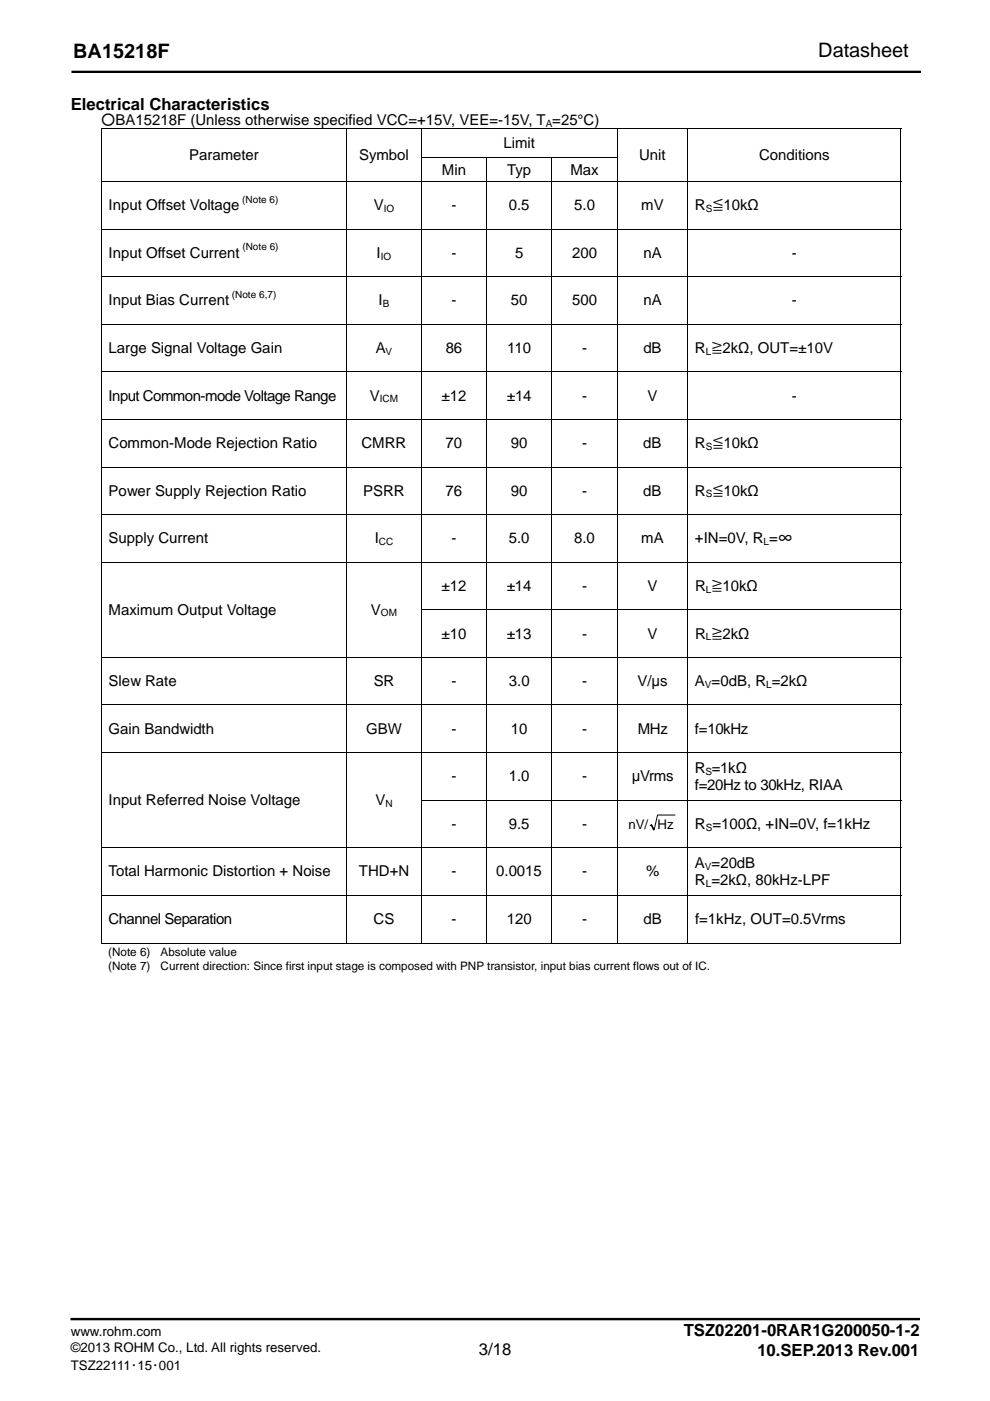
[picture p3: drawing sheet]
<svg xmlns="http://www.w3.org/2000/svg" width="210mm" height="297mm" viewBox="0 0 210 297" stroke-linecap="round" stroke-linejoin="round" font-family="sans-serif">
<defs><g id="words">
<g font-size="4.2">
<text x="15.5" y="12.4">BA15218F</text>
<text x="173.6" y="12.1">Datasheet</text>
</g>
<g font-size="3.5">
<text x="15" y="23.3">Electrical Characteristics</text>
<text x="101.6" y="287.3">3/18</text>
<text x="145" y="283.4">TSZ02201-0RAR1G200050-1-2</text>
<text x="160.6" y="287.4">10.SEP.2013 Rev.001</text>
</g>
<g font-size="3.2">
<text x="21.4" y="26.6">○BA15218F (Unless otherwise specified VCC=+15V, VEE=-15V, T =25°C)</text>
<text x="40.1" y="34">Parameter</text>
<text x="76.2" y="34">Symbol</text>
<text x="106.8" y="31.4">Limit</text>
<text x="135.6" y="34">Unit</text>
<text x="161" y="34">Conditions</text>
<text x="93.7" y="37">Min</text>
<text x="107.6" y="37">Typ</text>
<text x="121" y="37">Max</text>
<text x="23" y="44.6">Input Offset Voltage</text>
<text x="79.3" y="44.6">V</text>
<text x="95.8" y="44.6">-</text>
<text x="107.9" y="44.6">0.5</text>
<text x="121.8" y="44.6">5.0</text>
<text x="136" y="44.6">mV</text>
<text x="147.4" y="44.6">R ≦10kΩ</text>
<text x="23" y="54.7">Input Offset Current</text>
<text x="79.9" y="54.7">I</text>
<text x="95.8" y="54.7">-</text>
<text x="109.2" y="54.7">5</text>
<text x="121.3" y="54.7">200</text>
<text x="136.5" y="54.7">nA</text>
<text x="168" y="54.7">-</text>
<text x="23" y="64.7">Input Bias Current</text>
<text x="80.3" y="64.7">I</text>
<text x="95.8" y="64.7">-</text>
<text x="108.3" y="64.7">50</text>
<text x="121.3" y="64.7">500</text>
<text x="136.5" y="64.7">nA</text>
<text x="168" y="64.7">-</text>
<text x="23" y="74.8">Large Signal Voltage Gain</text>
<text x="79.7" y="74.8">A</text>
<text x="94.5" y="74.8">86</text>
<text x="107.6" y="74.8">110</text>
<text x="123.5" y="74.8">-</text>
<text x="136.5" y="74.8">dB</text>
<text x="147.4" y="74.8">R ≧2kΩ, OUT=±10V</text>
<text x="23" y="84.9">Input Common-mode Voltage Range</text>
<text x="78.4" y="84.9">V</text>
<text x="93.7" y="84.9">±12</text>
<text x="107.5" y="84.9">±14</text>
<text x="123.5" y="84.9">-</text>
<text x="137.4" y="84.9">V</text>
<text x="168" y="84.9">-</text>
<text x="23" y="95">Common-Mode Rejection Ratio</text>
<text x="76.7" y="95">CMRR</text>
<text x="94.5" y="95">70</text>
<text x="108.3" y="95">90</text>
<text x="123.5" y="95">-</text>
<text x="136.4" y="95">dB</text>
<text x="147.4" y="95">R ≦10kΩ</text>
<text x="23" y="105.1">Power Supply Rejection Ratio</text>
<text x="77" y="105.1">PSRR</text>
<text x="94.5" y="105.1">76</text>
<text x="108.3" y="105.1">90</text>
<text x="123.4" y="105.1">-</text>
<text x="136.4" y="105.1">dB</text>
<text x="147.4" y="105.1">R ≦10kΩ</text>
<text x="23" y="115.2">Supply Current</text>
<text x="79.5" y="115.2">I</text>
<text x="95.8" y="115.2">-</text>
<text x="107.9" y="115.2">5.0</text>
<text x="121.8" y="115.2">8.0</text>
<text x="136" y="115.2">mA</text>
<text x="147.4" y="115.2">+IN=0V, R =∞</text>
<text x="93.7" y="125.3">±12</text>
<text x="107.5" y="125.3">±14</text>
<text x="123.5" y="125.3">-</text>
<text x="137.4" y="125.3">V</text>
<text x="147.4" y="125.3">R ≧10kΩ</text>
<text x="23" y="130.3">Maximum Output Voltage</text>
<text x="78.7" y="130.3">V</text>
<text x="93.7" y="135.4">±10</text>
<text x="107.5" y="135.4">±13</text>
<text x="123.5" y="135.4">-</text>
<text x="137.4" y="135.4">V</text>
<text x="147.4" y="135.4">R ≧2kΩ</text>
<text x="23" y="145.5">Slew Rate</text>
<text x="79.3" y="145.5">SR</text>
<text x="95.8" y="145.5">-</text>
<text x="107.9" y="145.5">3.0</text>
<text x="123.5" y="145.5">-</text>
<text x="135.2" y="145.5">V/μs</text>
<text x="147.4" y="145.5">A =0dB, R =2kΩ</text>
<text x="23" y="155.6">Gain Bandwidth</text>
<text x="77.7" y="155.6">GBW</text>
<text x="95.8" y="155.6">-</text>
<text x="108.4" y="155.6">10</text>
<text x="123.5" y="155.6">-</text>
<text x="135.3" y="155.6">MHz</text>
<text x="147.4" y="155.6">f=10kHz</text>
<text x="95.8" y="165.6">-</text>
<text x="107.9" y="165.6">1.0</text>
<text x="123.5" y="165.6">-</text>
<text x="134" y="165.6">μVrms</text>
<text x="147.4" y="163.9">R =1kΩ</text>
<text x="147.4" y="167.4">f=20Hz to 30kHz, RIAA</text>
<text x="23" y="170.7">Input Referred Noise Voltage</text>
<text x="79.6" y="170.7">V</text>
<text x="95.8" y="175.7">-</text>
<text x="107.9" y="175.7">9.5</text>
<text x="123.5" y="175.7">-</text>
<text x="147.4" y="175.7">R =100Ω, +IN=0V, f=1kHz</text>
<text x="23" y="185.8">Total Harmonic Distortion + Noise</text>
<text x="76.1" y="185.8">THD+N</text>
<text x="95.7" y="185.8">-</text>
<text x="105.2" y="185.8">0.0015</text>
<text x="123.5" y="185.8">-</text>
<text x="137" y="185.8">%</text>
<text x="147.4" y="184.1">A =20dB</text>
<text x="147.4" y="187.7">R =2kΩ, 80kHz-LPF</text>
<text x="23" y="195.9">Channel Separation</text>
<text x="79.2" y="195.9">CS</text>
<text x="95.8" y="195.9">-</text>
<text x="107.5" y="195.9">120</text>
<text x="123.5" y="195.9">-</text>
<text x="136.5" y="195.9">dB</text>
<text x="147.4" y="195.9">f=1kHz, OUT=0.5Vrms</text>
</g>
<g font-size="2.8">
<text x="133.3" y="175.7">nV/ Hz</text>
<text x="15" y="283.4">www.rohm.com</text>
<text x="15" y="286.7">©2013 ROHM Co., Ltd. All rights reserved.</text>
<text x="15" y="290.4">TSZ22111･15･001</text>
</g>
<g font-size="2.5">
<text x="22.9" y="202.6">(Note 6)</text>
<text x="34.1" y="202.6">Absolute value</text>
<text x="22.9" y="205.8">(Note 7)</text>
<text x="34.1" y="205.8">Current direction: Since first input stage is composed with PNP transistor, input bias current flows out of IC.</text>
</g>
<g font-size="2.1">
<text x="115.7" y="27">A</text>
<text x="51.4" y="43">(Note 6)</text>
<text x="81.4" y="44.9">IO</text>
<text x="149.7" y="44.9">S</text>
<text x="51.4" y="53.1">(Note 6)</text>
<text x="80.8" y="55">IO</text>
<text x="49.2" y="63.2">(Note 6,7)</text>
<text x="81.2" y="65.1">B</text>
<text x="81.8" y="75.2">V</text>
<text x="149.7" y="75.2">L</text>
<text x="80.6" y="85.3">ICM</text>
<text x="149.7" y="95.4">S</text>
<text x="149.7" y="105.5">S</text>
<text x="80.4" y="115.6">CC</text>
<text x="161.9" y="115.6">L</text>
<text x="149.7" y="125.6">L</text>
<text x="80.8" y="130.7">OM</text>
<text x="149.7" y="135.7">L</text>
<text x="149.5" y="145.8">V</text>
<text x="162.5" y="145.8">L</text>
<text x="149.6" y="164.3">S</text>
<text x="81.7" y="171">N</text>
<text x="149.7" y="176.1">S</text>
<text x="149.5" y="184.5">V</text>
<text x="149.7" y="188">L</text>
</g>
</g></defs>
<path d="M15.3 15.2h179.9" fill="none" stroke="#000" stroke-width=".3"/>
<g fill="none" stroke="#000" stroke-width=".21">
<path d="M15.3 15.1h179.9v.3h-179.9zM21.4 27.3h169.8M21.4 38.5h169.8M21.5 27.4v6M21.5 33.4v5M21.5 38.5v10M73.5 27.4v6M73.5 33.4v5M73.5 38.5v10M89.3 33.4h41.7M89.4 27.4v6M89.4 33.4v5"/>
<path d="M89.4 38.5v10M103.2 33.4v5M103.2 38.5v10M117.1 33.4v5M117.1 38.5v10M130.9 27.4v6M130.9 33.4v5M130.9 38.5v10M145.9 27.4v6M145.9 33.4v5M145.9 38.5v10M191.1 27.4v6"/>
<path d="M191.1 33.4v5M191.1 38.5v10M21.4 48.6h169.8M21.4 58.7h169.8M21.5 48.6v10M21.5 58.7v10M73.5 48.6v10M73.5 58.7v10M89.4 48.6v10M89.4 58.7v10M103.2 48.6v10M103.2 58.7v10"/>
<path d="M117.1 48.6v10M117.1 58.7v10M130.9 48.6v10M130.9 58.7v10M145.9 48.6v10M145.9 58.7v10M191.1 48.6v10M191.1 58.7v10M21.4 68.7h169.8M21.4 78.8h169.8M21.5 68.8v10M21.5 78.9v10"/>
<path d="M73.5 68.8v10M73.5 78.9v10M89.4 68.8v10M89.4 78.9v10M103.2 68.8v10M103.2 78.9v10M117.1 68.8v10M117.1 78.9v10M130.9 68.8v10M130.9 78.9v10M145.9 68.8v10M145.9 78.9v10"/>
<path d="M191.1 68.8v10M191.1 78.9v10M21.4 88.9h169.8M21.4 99h169.8M21.5 89v10M21.5 99.1v10M73.5 89v10M73.5 99.1v10M89.4 89v10M89.4 99.1v10M103.2 89v10M103.2 99.1v10"/>
<path d="M117.1 89v10M117.1 99.1v10M130.9 89v10M130.9 99.1v10M145.9 89v10M145.9 99.1v10M191.1 89v10M191.1 99.1v10M21.4 109.1h169.8M21.4 119.2h169.8M21.5 109.2v9.9M21.5 119.2v10"/>
<path d="M73.5 109.2v9.9M73.5 119.2v10M89.4 109.2v9.9M89.4 119.2v10M103.2 109.2v9.9M103.2 119.2v10M117.1 109.2v9.9M117.1 119.2v10M130.9 109.2v9.9M130.9 119.2v10M145.9 109.2v9.9M145.9 119.2v10"/>
<path d="M191.1 109.2v9.9M191.1 119.2v10M21.4 139.4h169.8M21.5 129.3v10M21.5 139.4v10M73.5 129.3v10M73.5 139.4v10M89.3 129.3h101.9M89.4 129.3v10M89.4 139.4v10M103.2 129.3v10M103.2 139.4v10"/>
<path d="M117.1 129.3v10M117.1 139.4v10M130.9 129.3v10M130.9 139.4v10M145.9 129.3v10M145.9 139.4v10M191.1 129.3v10M191.1 139.4v10M21.4 149.5h169.8M21.4 159.6h169.8M21.5 149.5v10M21.5 159.6v10"/>
<path d="M73.5 149.5v10M73.5 159.6v10M89.4 149.5v10M89.4 159.6v10M103.2 149.5v10M103.2 159.6v10M117.1 149.5v10M117.1 159.6v10M130.9 149.5v10M130.9 159.6v10M145.9 149.5v10M145.9 159.6v10"/>
<path d="M191.1 149.5v10M191.1 159.6v10M21.4 179.7h169.8M21.5 169.7v10M21.5 179.8v10M73.5 169.7v10M73.5 179.8v10M89.3 169.7h101.9M89.4 169.7v10M89.4 179.8v10M103.2 169.7v10M103.2 179.8v10"/>
<path d="M117.1 169.7v10M117.1 179.8v10M130.9 169.7v10M130.9 179.8v10M138.2 174.9l-.3 .2M143.2 172.8h-3.7l-.8 3.1M145.9 169.7v10M145.9 179.8v10M191.1 169.7v10M191.1 179.8v10M21.4 189.8h169.8M21.4 200h169.6"/>
<path d="M21.5 189.9v10.1M73.5 189.9v10M89.4 189.9v10M103.2 189.9v10M117.1 189.9v10M130.9 189.9v10M145.9 189.9v10M191.1 189.9v10.1M15 279.5h180v.3h-180z"/>
</g>
<path d="M15.1 279.7h179.9" fill="none" stroke="#000" stroke-width=".28"/>
<path d="M21.4 27.2h.2v.2h-.2zM21.4 33.4h.2zM73.5 33.4h.1zM191 27.2h.2v.2h-.2zM191 33.4h.2zM21.4 129.2l.2 .1zM73.5 129.2l.1 .1zM21.4 169.6l.2 .1zM73.5 169.6l.1 .1zM191 199.9h.2v.1h-.2z" fill="#000"/>
<path d="M138.2 174.9l.5 1" fill="none" stroke="#000" stroke-width=".35"/>
<use href="#words"/>
</svg>
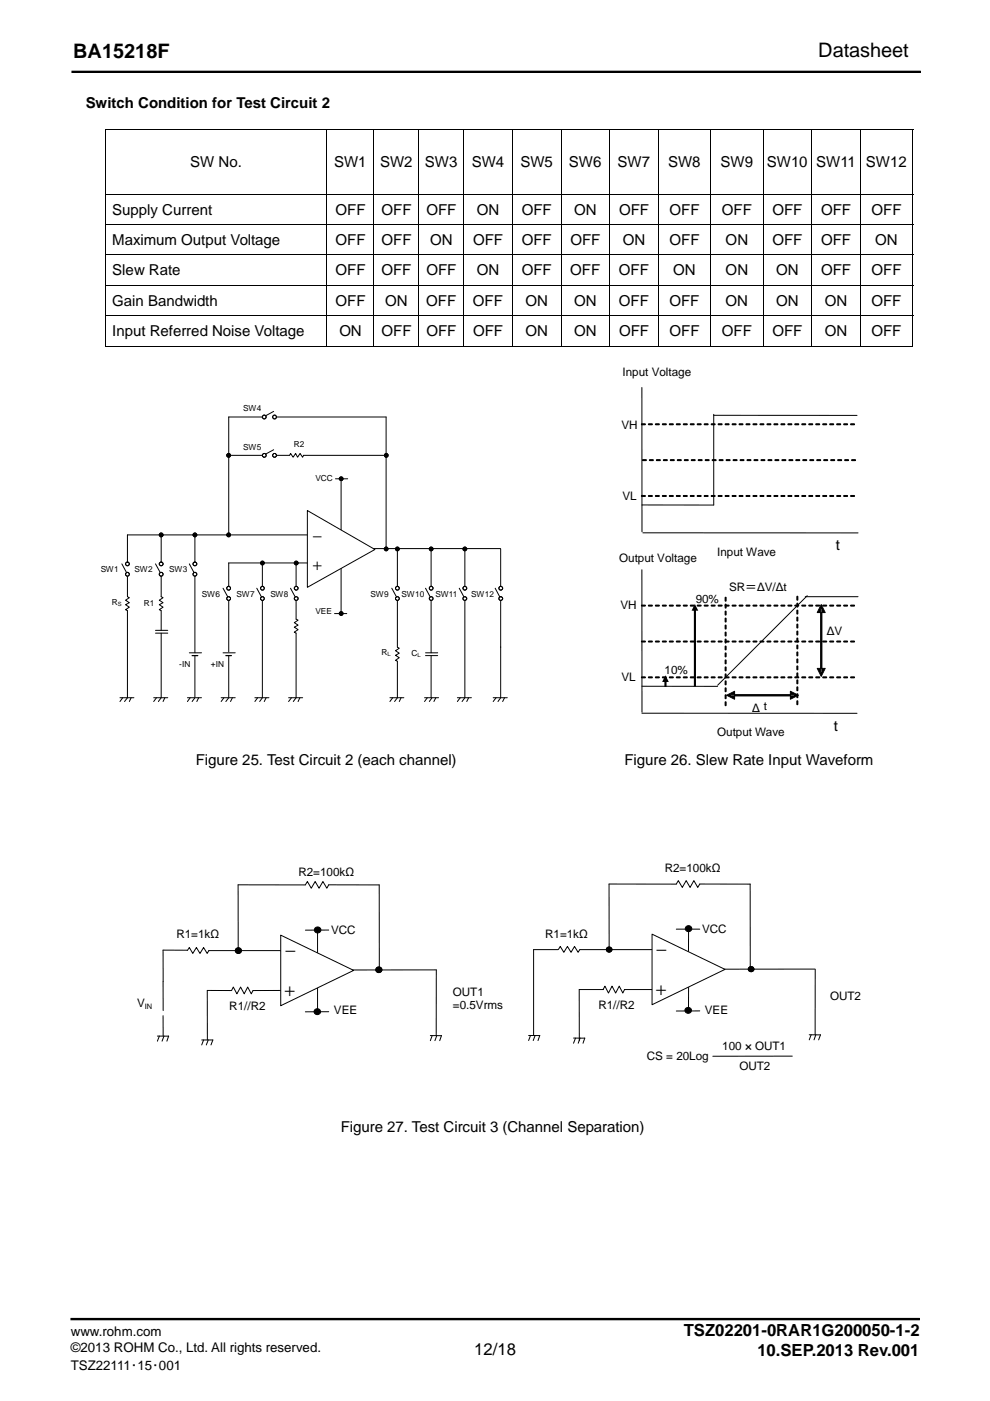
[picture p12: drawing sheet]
<svg xmlns="http://www.w3.org/2000/svg" width="210mm" height="297mm" viewBox="0 0 210 297" stroke-linecap="round" stroke-linejoin="round" font-family="sans-serif">
<defs><g id="words">
<g font-size="4.2">
<text x="15.5" y="12.4">BA15218F</text>
<text x="173.6" y="12.1">Datasheet</text>
</g>
<g font-size="3.5">
<text x="100.6" y="287.3">12/18</text>
<text x="145" y="283.4">TSZ02201-0RAR1G200050-1-2</text>
<text x="160.6" y="287.4">10.SEP.2013 Rev.001</text>
</g>
<g font-size="3.2">
<text x="18.2" y="22.9">Switch Condition for Test Circuit 2</text>
<text x="40.4" y="35.4">SW No.</text>
<text x="70.9" y="35.4">SW1</text>
<text x="80.6" y="35.4">SW2</text>
<text x="90.1" y="35.4">SW3</text>
<text x="100" y="35.4">SW4</text>
<text x="110.4" y="35.4">SW5</text>
<text x="120.7" y="35.4">SW6</text>
<text x="131" y="35.4">SW7</text>
<text x="141.7" y="35.4">SW8</text>
<text x="152.8" y="35.4">SW9</text>
<text x="162.7" y="35.4">SW10 SW11 SW12</text>
<text x="23.8" y="45.5">Supply Current</text>
<text x="71.2" y="45.5">OFF</text>
<text x="80.9" y="45.5">OFF</text>
<text x="90.4" y="45.5">OFF</text>
<text x="101.1" y="45.5">ON</text>
<text x="110.7" y="45.5">OFF</text>
<text x="121.8" y="45.5">ON</text>
<text x="131.3" y="45.5">OFF</text>
<text x="142" y="45.5">OFF</text>
<text x="153.1" y="45.5">OFF</text>
<text x="163.8" y="45.5">OFF</text>
<text x="174.2" y="45.5">OFF</text>
<text x="184.9" y="45.5">OFF</text>
<text x="23.8" y="51.9">Maximum Output Voltage</text>
<text x="71.2" y="51.9">OFF</text>
<text x="80.9" y="51.9">OFF</text>
<text x="91.2" y="51.9">ON</text>
<text x="100.3" y="51.9">OFF</text>
<text x="110.7" y="51.9">OFF</text>
<text x="121" y="51.9">OFF</text>
<text x="132.1" y="51.9">ON</text>
<text x="142" y="51.9">OFF</text>
<text x="153.9" y="51.9">ON</text>
<text x="163.8" y="51.9">OFF</text>
<text x="174.2" y="51.9">OFF</text>
<text x="185.6" y="51.9">ON</text>
<text x="23.8" y="58.4">Slew Rate</text>
<text x="71.2" y="58.4">OFF</text>
<text x="80.9" y="58.4">OFF</text>
<text x="90.4" y="58.4">OFF</text>
<text x="101.1" y="58.4">ON</text>
<text x="110.7" y="58.4">OFF</text>
<text x="121" y="58.4">OFF</text>
<text x="131.3" y="58.4">OFF</text>
<text x="142.8" y="58.4">ON</text>
<text x="153.9" y="58.4">ON</text>
<text x="164.6" y="58.4">ON</text>
<text x="174.2" y="58.4">OFF</text>
<text x="184.9" y="58.4">OFF</text>
<text x="23.8" y="64.8">Gain Bandwidth</text>
<text x="71.2" y="64.8">OFF</text>
<text x="81.7" y="64.8">ON</text>
<text x="90.4" y="64.8">OFF</text>
<text x="100.3" y="64.8">OFF</text>
<text x="111.4" y="64.8">ON</text>
<text x="121.7" y="64.8">ON</text>
<text x="131.3" y="64.8">OFF</text>
<text x="142" y="64.8">OFF</text>
<text x="153.9" y="64.8">ON</text>
<text x="164.6" y="64.8">ON</text>
<text x="175" y="64.8">ON</text>
<text x="184.8" y="64.8">OFF</text>
<text x="23.8" y="71.3">Input Referred Noise Voltage</text>
<text x="72" y="71.3">ON</text>
<text x="80.9" y="71.3">OFF</text>
<text x="90.4" y="71.3">OFF</text>
<text x="100.3" y="71.3">OFF</text>
<text x="111.5" y="71.3">ON</text>
<text x="121.8" y="71.3">ON</text>
<text x="131.3" y="71.3">OFF</text>
<text x="142" y="71.3">OFF</text>
<text x="153.1" y="71.3">OFF</text>
<text x="163.8" y="71.3">OFF</text>
<text x="175" y="71.3">ON</text>
<text x="184.8" y="71.3">OFF</text>
<text x="177.2" y="116.7">t</text>
<text x="176.8" y="154.9">t</text>
<text x="41.5" y="162.3">Figure 25. Test Circuit 2 (each channel)</text>
<text x="132.4" y="162.2">Figure 26. Slew Rate Input Waveform</text>
<text x="72.3" y="239.9">Figure 27. Test Circuit 3 (Channel Separation)</text>
</g>
<g font-size="2.8">
<text x="60.2" y="202.7">－</text>
<text x="138.9" y="202.5">－</text>
<text x="60.1" y="211.2">＋</text>
<text x="138.9" y="211">＋</text>
<text x="15" y="283.4">www.rohm.com</text>
<text x="15" y="286.7">©2013 ROHM Co., Ltd. All rights reserved.</text>
<text x="15" y="290.4">TSZ22111･15･001</text>
</g>
<g font-size="2.5">
<text x="132" y="79.8">Input Voltage</text>
<text x="131.8" y="90.9">VH</text>
<text x="132" y="106.1">VL</text>
<text x="66.1" y="114.6">－</text>
<text x="131.3" y="119.2">Output Voltage</text>
<text x="152.1" y="117.9">Input Wave</text>
<text x="66.1" y="120.8">＋</text>
<text x="154.6" y="125.3">SR＝ΔV/Δt</text>
<text x="131.6" y="129.1">VH</text>
<text x="147.6" y="127.9">90%</text>
<text x="175.3" y="134.6">ΔV</text>
<text x="140.9" y="143">10%</text>
<text x="131.8" y="144.3">VL</text>
<text x="159.5" y="150.9">Δ t</text>
<text x="152.1" y="156.1">Output Wave</text>
<text x="63.3" y="185.7">R2=100kΩ</text>
<text x="141" y="184.8">R2=100kΩ</text>
<text x="70.2" y="198">VCC</text>
<text x="148.9" y="197.7">VCC</text>
<text x="37.4" y="198.8">R1=1kΩ</text>
<text x="115.6" y="198.9">R1=1kΩ</text>
<text x="29.1" y="213.5">V</text>
<text x="48.6" y="214.2">R1//R2</text>
<text x="70.8" y="215.1">VEE</text>
<text x="96.1" y="211.1">OUT1</text>
<text x="96.1" y="213.8">=0.5Vrms</text>
<text x="126.9" y="213.8">R1//R2</text>
<text x="149.5" y="214.9">VEE</text>
<text x="176.1" y="212">OUT2</text>
<text x="137.2" y="224.7">CS = 20Log</text>
<text x="153.2" y="222.6">100 × OUT1</text>
<text x="156.8" y="226.8">OUT2</text>
</g>
<g font-size="1.8">
<text x="51.6" y="87.2">SW4</text>
<text x="51.6" y="95.5">SW5</text>
<text x="62.3" y="94.7">R2</text>
<text x="66.9" y="102">VCC</text>
<text x="21.4" y="121.3">SW1</text>
<text x="28.5" y="121.3">SW2</text>
<text x="35.9" y="121.3">SW3</text>
<text x="23.7" y="128.3">R</text>
<text x="30.5" y="128.4">R1</text>
<text x="42.8" y="126.5">SW6</text>
<text x="50.2" y="126.5">SW7</text>
<text x="57.3" y="126.5">SW8</text>
<text x="66.9" y="130.2">VEE</text>
<text x="78.6" y="126.7">SW9</text>
<text x="85.2" y="126.7">SW10</text>
<text x="92.4" y="126.7">SW11</text>
<text x="99.9" y="126.7">SW12</text>
<text x="38" y="141.4">-IN</text>
<text x="44.7" y="141.4">+IN</text>
<text x="80.9" y="138.9">R</text>
<text x="87.2" y="139.1">C</text>
</g>
<text font-size="1.6" x="30.7" y="213.8">IN</text>
<g font-size="1.2">
<text x="25" y="128.5">S</text>
<text x="82.2" y="139.1">L</text>
<text x="88.5" y="139.2">L</text>
</g>
</g></defs>
<path d="M15.3 15.2h179.9" fill="none" stroke="#000" stroke-width=".3"/>
<g fill="none" stroke="#000" stroke-width=".21">
<path d="M15.3 15.1h179.9v.3h-179.9zM22.2 27.4h171.5M22.3 27.5v4M22.3 31.5v9.6M69.3 27.5v4M69.3 31.5v9.6M79.3 27.5v4M79.3 31.5v9.6M88.8 27.5v4M88.8 31.5v9.6M98.4 27.5v4M98.4 31.5v9.6"/>
<path d="M108.7 27.5v4M108.7 31.5v9.6M119 27.5v4M119 31.5v9.6M129.3 27.5v4M129.3 31.5v9.6M139.6 27.5v4M139.6 31.5v9.6M150.7 27.5v4M150.7 31.5v9.6M161.9 27.5v4M161.9 31.5v9.6"/>
<path d="M172.2 27.5v4M172.2 31.5v9.6M182.5 27.5v4M182.5 31.5v9.6M193.6 27.5v4M193.6 31.5v9.6M22.2 41.2h171.5M22.2 47.6h171.5M22.2 54.1h171.5M22.3 41.2v6.4M22.3 47.6v6.4M22.3 54.1v6.4"/>
<path d="M69.3 41.2v6.4M69.3 47.6v6.4M69.3 54.1v6.4M79.3 41.2v6.4M79.3 47.6v6.4M79.3 54.1v6.4M88.8 41.2v6.4M88.8 47.6v6.4M88.8 54.1v6.4M98.4 41.2v6.4M98.4 47.6v6.4M98.4 54.1v6.4"/>
<path d="M108.7 41.2v6.4M108.7 47.6v6.4M108.7 54.1v6.4M119 41.2v6.4M119 47.6v6.4M119 54.1v6.4M129.3 41.2v6.4M129.3 47.6v6.4M129.3 54.1v6.4M139.6 41.2v6.4M139.6 47.6v6.4M139.6 54.1v6.4"/>
<path d="M150.7 41.2v6.4M150.7 47.6v6.4M150.7 54.1v6.4M161.9 41.2v6.4M161.9 47.6v6.4M161.9 54.1v6.4M172.2 41.2v6.4M172.2 47.6v6.4M172.2 54.1v6.4M182.5 41.2v6.4M182.5 47.6v6.4M182.5 54.1v6.4"/>
<path d="M193.6 41.2v6.4M193.6 47.6v6.4M193.6 54.1v6.4M22.2 60.5h171.5M22.2 66.9h171.5M22.2 73.4h171.3M22.3 60.5v6.4M22.3 67v6.5M69.3 60.5v6.4M69.3 67v6.3M79.3 60.5v6.4M79.3 67v6.3"/>
<path d="M88.8 60.5v6.4M88.8 67v6.3M98.4 60.5v6.4M98.4 67v6.3M108.7 60.5v6.4M108.7 67v6.3M119 60.5v6.4M119 67v6.3M129.3 60.5v6.4M129.3 67v6.3M139.6 60.5v6.4M139.6 67v6.3"/>
<path d="M150.7 60.5v6.4M150.7 67v6.3M161.9 60.5v6.4M161.9 67v6.3M172.2 60.5v6.4M172.2 67v6.3M182.5 60.5v6.4M182.5 67v6.3M193.6 60.5v6.4M193.6 67v6.5M136.1 89.9l.8 .1-.8 .1zM136.1 82.1l.1 30.7"/>
<path d="M136.3 97.5l.8 .1-.7 .1zM137.6 89.9l.8 .1-.8 .1zM137.8 97.5l.8 .1-.8 .1zM139 89.9l.8 .1-.7 .1zM139.3 97.5l.8 .1-.8 .1zM140.5 89.9l.8 .1-.7 .1zM140.7 97.5l.8 .1-.7 .1zM142 89.9l.8 .1-.7 .1zM142.2 97.5l.8 .1-.7 .1zM143.5 89.9l.8 .1-.7 .1zM143.7 97.5l.8 .1-.7 .1zM145 89.9l.8 .1-.8 .1z"/>
<path d="M145.2 97.5l.8 .1-.8 .1zM146.4 89.9l.8 .1-.7 .1zM146.7 97.5l.7 .1-.7 .1zM147.9 89.9l.8 .1-.7 .1zM148.1 97.5l.8 .1-.7 .1zM149.4 89.9l.8 .1-.7 .1zM149.6 97.5l.8 .1-.7 .1zM150.9 89.9l.8 .1-.8 .1zM151.1 97.5l.8 .1-.7 .1zM151.4 87.8v19.3h-15.3M151.4 88.1h30.4M152.3 89.9l.9 .1-.8 .1z"/>
<path d="M152.6 97.5l.8 .1-.8 .1zM153.8 89.9l.8 .1-.7 .1zM154 97.5l.9 .1-.8 .1zM155.3 89.9l.8 .1-.7 .1zM155.5 97.5l.8 .1-.7 .1zM156.8 89.9l.8 .1-.7 .1zM157 97.5l.8 .1-.7 .1zM158.3 89.9l.8 .1-.8 .1zM158.5 97.5l.8 .1-.8 .1zM159.7 89.9l.8 .1-.7 .1zM160 97.5l.8 .1-.8 .1zM161.2 89.9l.8 .1-.7 .1z"/>
<path d="M161.4 97.5l.8 .1-.7 .1zM162.7 89.9l.8 .1-.7 .1zM162.9 97.5l.8 .1-.7 .1zM164.2 89.9l.8 .1-.7 .1zM164.4 97.5l.8 .1-.7 .1zM165.7 89.9l.8 .1-.8 .1zM165.9 97.5l.8 .1-.8 .1zM167.1 89.9l.9 .1-.8 .1zM167.4 97.5l.8 .1-.8 .1zM168.6 89.9l.8 .1-.7 .1zM168.8 97.5l.8 .1-.7 .1zM170.1 89.9l.8 .1-.7 .1z"/>
<path d="M170.3 97.5l.8 .1-.7 .1zM171.6 89.9l.8 .1-.8 .1zM171.8 97.5l.8 .1-.7 .1zM173.1 89.9l.8 .1-.8 .1zM173.3 97.5l.8 .1-.8 .1zM174.5 89.9l.8 .1-.7 .1zM174.7 97.5l.9 .1-.8 .1zM176 89.9l.8 .1-.7 .1zM176.2 97.5l.8 .1-.7 .1zM177.5 89.9l.8 .1-.7 .1zM177.7 97.5l.8 .1-.7 .1zM179 89.9l.8 .1-.8 .1z"/>
<path d="M179.2 97.5l.8 .1-.7 .1zM180.4 89.9l.9 .1-.8 .1zM180.7 97.5l.8 .1-.8 .1zM27 113.4h43M41.3 113.4v6M48.5 119.4h22.9M72.2 116.3h34M72.3 101.5v28.2M136.1 105.1l.8 .1-.8 .1zM136.4 113h45.6M137.6 105.1l.8 .1-.8 .1zM139 105.1l.8 .1-.7 .1z"/>
<path d="M140.5 105.1l.8 .1-.7 .1zM142 105.1l.8 .1-.7 .1zM143.5 105.1l.8 .1-.7 .1zM145 105.1l.8 .1-.8 .1zM146.4 105.1l.8 .1-.7 .1zM147.9 105.1l.8 .1-.7 .1zM149.4 105.1l.8 .1-.7 .1zM150.9 105.1l.8 .1-.8 .1zM152.3 105.1l.9 .1-.8 .1zM153.8 105.1l.8 .1-.7 .1zM155.3 105.1l.8 .1-.7 .1zM156.8 105.1l.8 .1-.7 .1z"/>
<path d="M158.3 105.1l.8 .1-.8 .1zM159.7 105.1l.8 .1-.7 .1zM161.2 105.1l.8 .1-.7 .1zM162.7 105.1l.8 .1-.7 .1zM164.2 105.1l.8 .1-.7 .1zM165.7 105.1l.8 .1-.8 .1zM167.1 105.1l.9 .1-.8 .1zM168.6 105.1l.8 .1-.7 .1zM170.1 105.1l.8 .1-.7 .1zM171.6 105.1l.8 .1-.8 .1zM173.1 105.1l.8 .1-.8 .1zM174.5 105.1l.8 .1-.7 .1z"/>
<path d="M176 105.1l.8 .1-.7 .1zM177.5 105.1l.8 .1-.7 .1zM179 105.1l.8 .1-.8 .1zM180.4 105.1l.9 .1-.8 .1zM33 133.6h2.6M34.2 121.8v4.7M34.2 134.2v13.7M40.2 138.4h2.5M41.3 121.5v16.9M98.6 126.9v21M136.1 128.3l.8 .1-.8 .1zM136.1 135.9l.8 .1-.8 .1z"/>
<path d="M136.1 120.8l.1 30.2M137.6 128.3l.8 .1-.8 .1zM137.6 135.9l.8 .1-.8 .1zM139 128.3l.8 .1-.7 .1zM139 135.9l.8 .1-.7 .1zM140.5 128.3l.8 .1-.7 .1zM140.5 135.9l.8 .1-.7 .1zM142 128.3l.8 .1-.7 .1zM142 135.9l.8 .1-.7 .1zM143.5 128.3l.8 .1-.7 .1zM143.5 135.9l.8 .1-.7 .1zM145 128.3l.8 .1-.8 .1z"/>
<path d="M145 135.9l.8 .1-.8 .1zM146.4 128.3l.8 .1-.7 .1zM146.4 135.9l.8 .1-.7 .1zM147.9 128.3l.8 .1-.7 .1zM147.9 135.9l.8 .1-.7 .1zM149.4 128.3l.8 .1-.7 .1zM149.4 135.9l.8 .1-.7 .1zM150.9 128.3l.8 .1-.8 .1zM150.9 135.9l.8 .1-.8 .1zM152.3 128.3l.9 .1-.8 .1zM152.3 135.9l.9 .1-.8 .1zM153.8 126.6l.2 .1-.1 .8z"/>
<path d="M153.8 128.1l.2 .1-.1 .7zM153.8 129.6l.2 .1-.1 .7zM153.8 131.1h.2l-.1 .8zM153.8 132.6h.2l-.1 .8zM153.8 134l.2 .1-.1 .8zM153.8 135.5l.2 .1-.1 .7zM153.8 137l.2 .1-.1 .7zM153.8 138.5h.2l-.1 .8zM153.8 139.9l.2 .1-.1 .8zM153.8 128.3l.8 .1-.7 .1zM153.8 135.9l.8 .1-.7 .1zM155.3 128.3l.8 .1-.7 .1z"/>
<path d="M155.3 135.9l.8 .1-.7 .1zM156.8 128.3l.8 .1-.7 .1zM156.8 135.9l.8 .1-.7 .1zM158.3 128.3l.8 .1-.8 .1zM158.3 135.9l.8 .1-.8 .1zM159.7 128.3l.8 .1-.7 .1zM159.7 135.9l.8 .1-.7 .1zM161.2 128.3l.8 .1-.7 .1zM161.2 135.9l.8 .1-.7 .1zM162.7 128.3l.8 .1-.7 .1zM162.7 135.9l.8 .1-.7 .1zM164.2 128.3l.8 .1-.7 .1z"/>
<path d="M164.2 135.9l.8 .1-.7 .1zM165.7 128.3l.8 .1-.8 .1zM165.7 135.9l.8 .1-.8 .1zM167.1 128.3l.9 .1-.8 .1zM167.1 135.9l.9 .1-.8 .1zM168.6 128.3l.8 .1-.7 .1zM168.6 135.9l.8 .1-.7 .1zM169 126.4l.2 .1-.1 .8zM169 127.9l.2 .1-.1 .7zM169 129.4l.2 .1-.1 .7zM169 130.9h.2l-.1 .8zM169 132.3l.2 .1-.1 .8z"/>
<path d="M169 133.8l.2 .1-.1 .7zM169 135.3l.2 .1-.1 .7zM169 136.8l.2 .1-.1 .7zM169 138.3h.2l-.1 .8zM169 139.7l.2 .1-.1 .7zM170.1 128.3l.8 .1-.7 .1zM170.1 135.9l.8 .1-.7 .1zM170.8 126.5h11.2M171.2 126.3l-19 19M171.6 128.3l.8 .1-.8 .1zM171.6 135.9l.8 .1-.8 .1zM173.1 128.3l.8 .1-.8 .1z"/>
<path d="M173.1 135.9l.8 .1-.8 .1zM174.1 129l.2 .1v13.4l-.1 .1-.1-.1zM174.2 128.2l.8 1.7h-1.7zM174.5 128.3l.8 .1-.7 .1zM174.5 135.9l.8 .1-.7 .1zM176 128.3l.8 .1-.7 .1zM176 135.9l.8 .1-.7 .1zM177.5 128.3l.8 .1-.7 .1zM177.5 135.9l.8 .1-.7 .1zM179 128.3l.8 .1-.8 .1zM179 135.9l.8 .1-.8 .1zM180.4 128.3l.9 .1-.8 .1z"/>
<path d="M180.4 135.9l.9 .1-.8 .1zM136.1 143.5l.8 .1-.8 .1zM136.1 145.5h16.1M136.1 151.2h45.7M137.6 143.5l.8 .1-.8 .1zM139 143.5l.8 .1-.7 .1zM140.5 143.5l.8 .1-.7 .1zM142 143.5l.8 .1-.7 .1zM143.5 143.5l.8 .1-.7 .1zM145 143.5l.8 .1-.8 .1zM146.4 143.5l.8 .1-.7 .1zM147.9 143.5l.8 .1-.7 .1z"/>
<path d="M149.4 143.5l.8 .1-.7 .1zM150.9 143.5l.8 .1-.8 .1zM152.3 143.5l.9 .1-.8 .1zM153.8 141.4l.2 .1-.1 .7zM153.8 142.9l.2 .1-.1 .7zM153.8 144.4l.2 .1-.1 .7zM153.8 145.9h.2l-.1 .8zM153.8 147.3l.2 .1-.1 .7zM153.8 148.8l.2 .1-.1 .7zM153.8 143.5l.8 .1-.7 .1zM154.1 147.4l1.7-.8v1.7zM155 147.3h13.4l.2 .1-.2 .2h-13.3z"/>
<path d="M155.3 143.5l.8 .1-.7 .1zM156.8 143.5l.8 .1-.7 .1zM158.3 143.5l.8 .1-.8 .1zM159.7 143.5l.8 .1-.7 .1zM161.2 143.5l.8 .1-.7 .1zM162.7 143.5l.8 .1-.7 .1zM164.2 143.5l.8 .1-.7 .1zM165.7 143.5l.8 .1-.8 .1zM167.1 143.5l.9 .1-.8 .1zM167.6 146.6l1.7 .8-1.7 .9zM168.6 143.5l.8 .1-.7 .1zM169 141.2l.2 .1-.1 .7z"/>
<path d="M169 142.7l.2 .1-.1 .7zM169 144.2l.2 .1-.1 .7zM169 145.7h.2l-.1 .8zM169 147.1l.2 .1-.1 .7zM169 148.6l.2 .1-.1 .7zM170.1 143.5l.8 .1-.7 .1zM171.6 143.5l.8 .1-.8 .1zM173.1 143.5l.8 .1-.8 .1zM173.3 141.7h1.7l-.8 1.7zM174.5 143.5l.8 .1-.7 .1zM176 143.5l.8 .1-.7 .1zM177.5 143.5l.8 .1-.7 .1z"/>
<path d="M179 143.5l.8 .1-.8 .1zM180.4 143.5l.9 .1-.8 .1zM15 279.5h180v.3h-180z"/>
</g>
<path d="M15.1 279.7h179.9" fill="none" stroke="#000" stroke-width=".28"/>
<g fill="#000">
<path d="M22.2 27.3h.2v.2h-.2zM22.2 31.5h.2zM69.3 31.5h.1zM79.3 31.5h.1zM88.8 31.5h.1zM98.3 31.5h.1zM108.6 31.5h.1zM139.6 31.5h.1zM150.7 31.5h.1zM161.8 31.5h.1zM172.1 31.5h.1zM193.5 27.3h.2v.2h-.2z"/>
<path d="M193.5 31.5h.2zM193.5 73.3h.2v.2h-.2z"/>
<path d="M140.9 144.2h.5v1.4h-.5zM141.1 143.2l.8 1.4h-1.5z"/>
<path d="M147.2 129.1h.4v16.5h-.4zM147.4 128.1l.7 1.4h-1.4z"/>
</g>
<g fill="#000">
<path d="M136.1 89.9l.8 .1-.8 .1zM137.6 89.9l.8 .1-.8 .1zM139 89.9l.8 .1-.7 .1zM140.5 89.9l.8 .1-.7 .1zM142 89.9l.8 .1-.7 .1zM143.5 89.9l.8 .1-.7 .1zM145 89.9l.8 .1-.8 .1zM146.4 89.9l.8 .1-.7 .1zM147.9 89.9l.8 .1-.7 .1zM149.4 89.9l.8 .1-.7 .1zM150.9 89.9l.8 .1-.8 .1zM152.3 89.9l.9 .1-.8 .1zM153.8 89.9l.8 .1-.7 .1zM155.3 89.9l.8 .1-.7 .1zM156.8 89.9l.8 .1-.7 .1zM158.3 89.9l.8 .1-.8 .1zM159.7 89.9l.8 .1-.7 .1zM161.2 89.9l.8 .1-.7 .1zM162.7 89.9l.8 .1-.7 .1zM164.2 89.9l.8 .1-.7 .1zM165.7 89.9l.8 .1-.8 .1zM167.1 89.9l.9 .1-.8 .1zM168.6 89.9l.8 .1-.7 .1zM170.1 89.9l.8 .1-.7 .1zM171.6 89.9l.8 .1-.8 .1zM173.1 89.9l.8 .1-.8 .1zM174.5 89.9l.8 .1-.7 .1zM176 89.9l.8 .1-.7 .1zM177.5 89.9l.8 .1-.7 .1zM179 89.9l.8 .1-.8 .1zM180.4 89.9l.9 .1-.8 .1z" fill-rule="evenodd"/>
<path d="M136.3 97.5l.8 .1-.7 .1zM137.8 97.5l.8 .1-.8 .1zM139.3 97.5l.8 .1-.8 .1zM140.7 97.5l.8 .1-.7 .1zM142.2 97.5l.8 .1-.7 .1zM143.7 97.5l.8 .1-.7 .1zM145.2 97.5l.8 .1-.8 .1zM146.7 97.5l.7 .1-.7 .1zM148.1 97.5l.8 .1-.7 .1zM149.6 97.5l.8 .1-.7 .1zM151.1 97.5l.8 .1-.7 .1zM152.6 97.5l.8 .1-.8 .1zM154 97.5l.9 .1-.8 .1zM155.5 97.5l.8 .1-.7 .1zM157 97.5l.8 .1-.7 .1zM158.5 97.5l.8 .1-.8 .1zM160 97.5l.8 .1-.8 .1zM161.4 97.5l.8 .1-.7 .1zM162.9 97.5l.8 .1-.7 .1zM164.4 97.5l.8 .1-.7 .1zM165.9 97.5l.8 .1-.8 .1zM167.4 97.5l.8 .1-.8 .1zM168.8 97.5l.8 .1-.7 .1zM170.3 97.5l.8 .1-.7 .1zM171.8 97.5l.8 .1-.7 .1zM173.3 97.5l.8 .1-.8 .1zM174.7 97.5l.9 .1-.8 .1zM176.2 97.5l.8 .1-.7 .1zM177.7 97.5l.8 .1-.7 .1zM179.2 97.5l.8 .1-.7 .1zM180.7 97.5l.8 .1-.8 .1z" fill-rule="evenodd"/>
<path d="M136.1 105.1l.8 .1-.8 .1zM137.6 105.1l.8 .1-.8 .1zM139 105.1l.8 .1-.7 .1zM140.5 105.1l.8 .1-.7 .1zM142 105.1l.8 .1-.7 .1zM143.5 105.1l.8 .1-.7 .1zM145 105.1l.8 .1-.8 .1zM146.4 105.1l.8 .1-.7 .1zM147.9 105.1l.8 .1-.7 .1zM149.4 105.1l.8 .1-.7 .1zM150.9 105.1l.8 .1-.8 .1zM152.3 105.1l.9 .1-.8 .1zM153.8 105.1l.8 .1-.7 .1zM155.3 105.1l.8 .1-.7 .1zM156.8 105.1l.8 .1-.7 .1zM158.3 105.1l.8 .1-.8 .1zM159.7 105.1l.8 .1-.7 .1zM161.2 105.1l.8 .1-.7 .1zM162.7 105.1l.8 .1-.7 .1zM164.2 105.1l.8 .1-.7 .1zM165.7 105.1l.8 .1-.8 .1zM167.1 105.1l.9 .1-.8 .1zM168.6 105.1l.8 .1-.7 .1zM170.1 105.1l.8 .1-.7 .1zM171.6 105.1l.8 .1-.8 .1zM173.1 105.1l.8 .1-.8 .1zM174.5 105.1l.8 .1-.7 .1zM176 105.1l.8 .1-.7 .1zM177.5 105.1l.8 .1-.7 .1zM179 105.1l.8 .1-.8 .1zM180.4 105.1l.9 .1-.8 .1z" fill-rule="evenodd"/>
<path d="M136.1 128.3l.8 .1-.8 .1zM137.6 128.3l.8 .1-.8 .1zM139 128.3l.8 .1-.7 .1zM140.5 128.3l.8 .1-.7 .1zM142 128.3l.8 .1-.7 .1zM143.5 128.3l.8 .1-.7 .1zM145 128.3l.8 .1-.8 .1zM146.4 128.3l.8 .1-.7 .1zM147.9 128.3l.8 .1-.7 .1zM149.4 128.3l.8 .1-.7 .1zM150.9 128.3l.8 .1-.8 .1zM152.3 128.3l.9 .1-.8 .1zM153.8 128.3l.8 .1-.7 .1zM155.3 128.3l.8 .1-.7 .1zM156.8 128.3l.8 .1-.7 .1zM158.3 128.3l.8 .1-.8 .1zM159.7 128.3l.8 .1-.7 .1zM161.2 128.3l.8 .1-.7 .1zM162.7 128.3l.8 .1-.7 .1zM164.2 128.3l.8 .1-.7 .1zM165.7 128.3l.8 .1-.8 .1zM167.1 128.3l.9 .1-.8 .1zM168.6 128.3l.8 .1-.7 .1zM170.1 128.3l.8 .1-.7 .1zM171.6 128.3l.8 .1-.8 .1zM173.1 128.3l.8 .1-.8 .1zM174.5 128.3l.8 .1-.7 .1zM176 128.3l.8 .1-.7 .1zM177.5 128.3l.8 .1-.7 .1zM179 128.3l.8 .1-.8 .1zM180.4 128.3l.9 .1-.8 .1z" fill-rule="evenodd"/>
<path d="M136.1 135.9l.8 .1-.8 .1zM137.6 135.9l.8 .1-.8 .1zM139 135.9l.8 .1-.7 .1zM140.5 135.9l.8 .1-.7 .1zM142 135.9l.8 .1-.7 .1zM143.5 135.9l.8 .1-.7 .1zM145 135.9l.8 .1-.8 .1zM146.4 135.9l.8 .1-.7 .1zM147.9 135.9l.8 .1-.7 .1zM149.4 135.9l.8 .1-.7 .1zM150.9 135.9l.8 .1-.8 .1zM152.3 135.9l.9 .1-.8 .1zM153.8 135.9l.8 .1-.7 .1zM155.3 135.9l.8 .1-.7 .1zM156.8 135.9l.8 .1-.7 .1zM158.3 135.9l.8 .1-.8 .1zM159.7 135.9l.8 .1-.7 .1zM161.2 135.9l.8 .1-.7 .1zM162.7 135.9l.8 .1-.7 .1zM164.2 135.9l.8 .1-.7 .1zM165.7 135.9l.8 .1-.8 .1zM167.1 135.9l.9 .1-.8 .1zM168.6 135.9l.8 .1-.7 .1zM170.1 135.9l.8 .1-.7 .1zM171.6 135.9l.8 .1-.8 .1zM173.1 135.9l.8 .1-.8 .1zM174.5 135.9l.8 .1-.7 .1zM176 135.9l.8 .1-.7 .1zM177.5 135.9l.8 .1-.7 .1zM179 135.9l.8 .1-.8 .1zM180.4 135.9l.9 .1-.8 .1z" fill-rule="evenodd"/>
<path d="M153.8 126.6l.2 .1-.1 .8zM153.8 128.1l.2 .1-.1 .7zM153.8 129.6l.2 .1-.1 .7zM153.8 131.1h.2l-.1 .8zM153.8 132.6h.2l-.1 .8zM153.8 134l.2 .1-.1 .8zM153.8 135.5l.2 .1-.1 .7zM153.8 137l.2 .1-.1 .7zM153.8 138.5h.2l-.1 .8zM153.8 139.9l.2 .1-.1 .8zM153.8 141.4l.2 .1-.1 .7zM153.8 142.9l.2 .1-.1 .7zM153.8 144.4l.2 .1-.1 .7zM153.8 145.9h.2l-.1 .8zM153.8 147.3l.2 .1-.1 .7zM153.8 148.8l.2 .1-.1 .7z" fill-rule="evenodd"/>
<path d="M169 126.4l.2 .1-.1 .8zM169 127.9l.2 .1-.1 .7zM169 129.4l.2 .1-.1 .7zM169 130.9h.2l-.1 .8zM169 132.3l.2 .1-.1 .8zM169 133.8l.2 .1-.1 .7zM169 135.3l.2 .1-.1 .7zM169 136.8l.2 .1-.1 .7zM169 138.3h.2l-.1 .8zM169 139.7l.2 .1-.1 .7zM169 141.2l.2 .1-.1 .7zM169 142.7l.2 .1-.1 .7zM169 144.2l.2 .1-.1 .7zM169 145.7h.2l-.1 .8zM169 147.1l.2 .1-.1 .7zM169 148.6l.2 .1-.1 .7z" fill-rule="evenodd"/>
<path d="M136.1 143.5l.8 .1-.8 .1zM137.6 143.5l.8 .1-.8 .1zM139 143.5l.8 .1-.7 .1zM140.5 143.5l.8 .1-.7 .1zM142 143.5l.8 .1-.7 .1zM143.5 143.5l.8 .1-.7 .1zM145 143.5l.8 .1-.8 .1zM146.4 143.5l.8 .1-.7 .1zM147.9 143.5l.8 .1-.7 .1zM149.4 143.5l.8 .1-.7 .1zM150.9 143.5l.8 .1-.8 .1zM152.3 143.5l.9 .1-.8 .1zM153.8 143.5l.8 .1-.7 .1zM155.3 143.5l.8 .1-.7 .1zM156.8 143.5l.8 .1-.7 .1zM158.3 143.5l.8 .1-.8 .1zM159.7 143.5l.8 .1-.7 .1zM161.2 143.5l.8 .1-.7 .1zM162.7 143.5l.8 .1-.7 .1zM164.2 143.5l.8 .1-.7 .1zM165.7 143.5l.8 .1-.8 .1zM167.1 143.5l.9 .1-.8 .1zM168.6 143.5l.8 .1-.7 .1zM170.1 143.5l.8 .1-.7 .1zM171.6 143.5l.8 .1-.8 .1zM173.1 143.5l.8 .1-.8 .1zM174.5 143.5l.8 .1-.7 .1zM176 143.5l.8 .1-.7 .1zM177.5 143.5l.8 .1-.7 .1zM179 143.5l.8 .1-.8 .1zM180.4 143.5l.9 .1-.8 .1z" fill-rule="evenodd"/>
<path d="M155 147.3h13.4l.2 .1-.2 .2h-13.3zM154.1 147.4l1.7-.8v1.7zM167.6 146.6l1.7 .8-1.7 .9z" fill-rule="evenodd"/>
<path d="M174.1 129l.2 .1v13.4l-.1 .1-.1-.1zM173.3 141.7h1.7l-.8 1.7zM174.2 128.2l.8 1.7h-1.7z" fill-rule="evenodd"/>
</g>
<path d="M40.7 139h1.3" fill="none" stroke="#000" stroke-width=".26"/>
<path d="M65.2 108.2l14.3 8.3-14.3 8z" fill="#fff"/>
<g fill="none" stroke="#000" stroke-width=".21">
<path d="M27 113.4v6M33 119.5l1.2 2.3M34.2 113.4v6M65.2 108.2l14.3 8.3-14.3 8zM84.3 116.4v8.3M27 129.5v18.4l-.6 .8M33 134.2h2.6M34.2 126.5l.4 .2-.8 .6 .8 .5-.8 .4 .8 .5-.8 .6 .4 .2v4.1M71 130.1h2.6M84.3 127.1v10.1M91.4 126.7v11.7M25.4 147.9h3"/>
<path d="M26 147.9l-.6 .8M27.8 147.9l-.4 .8M32.6 147.9h3M33.2 147.9l-.6 .8M34.2 147.9l-.6 .8M35 147.9l-.4 .8M39.8 147.9h2.9M40.3 147.9l-.5 .8M41.3 147.9l-.6 .8M42.1 147.9l-.4 .8M82.7 147.9h3M83.3 147.9l-.6 .8"/>
<path d="M84.3 140.2v7.7l-.6 .8M85.1 147.9l-.4 .8M90 147.9h3M90.6 147.9l-.6 .8M91.6 147.9l-.5 .8M92.4 147.9l-.4 .8M97 147.9h3M97.6 147.9l-.6 .8M98.6 147.9l-.6 .8M99.4 147.9l-.4 .8"/>
<circle cx="34.2" cy="113.4" r=".4"/>
<circle cx="41.3" cy="113.4" r=".4"/>
<circle cx="72.4" cy="101.5" r=".39"/>
<circle cx="84.3" cy="116.4" r=".4"/>
<circle cx="91.5" cy="116.4" r=".39"/>
<circle cx="98.6" cy="116.4" r=".4"/>
<circle cx="72.4" cy="130.1" r=".39"/>
</g>
<g fill="#000">
<circle cx="34.2" cy="113.4" r=".4"/>
<circle cx="41.3" cy="113.4" r=".4"/>
<circle cx="72.4" cy="101.5" r=".39"/>
<circle cx="84.3" cy="116.4" r=".4"/>
<circle cx="91.5" cy="116.4" r=".39"/>
<circle cx="98.6" cy="116.4" r=".4"/>
<circle cx="72.4" cy="130.1" r=".39"/>
</g>
<circle cx="34.2" cy="119.6" r=".4" fill="#fff"/>
<circle cx="34.2" cy="119.6" r=".4" fill="none" stroke="#000" stroke-width=".21"/>
<circle cx="34.2" cy="121.8" r=".4" fill="#fff"/>
<g fill="none" stroke="#000" stroke-width=".21">
<path d="M40.2 119.5l1.1 2.3"/>
<circle cx="34.2" cy="121.8" r=".4"/>
</g>
<circle cx="41.3" cy="119.6" r=".4" fill="#fff"/>
<circle cx="41.3" cy="119.6" r=".4" fill="none" stroke="#000" stroke-width=".21"/>
<circle cx="41.3" cy="121.7" r=".4" fill="#fff"/>
<g fill="none" stroke="#000" stroke-width=".21">
<path d="M48.5 119.4v5.1M47.3 124.7l1.2 2.2v11.3M48.5 139v8.7M46.9 147.9h3M47.5 147.9l-.6 .8M48.5 147.9l-.6 .8M49.3 147.9l-.4 .8"/>
<circle cx="41.3" cy="121.7" r=".4"/>
</g>
<circle cx="48.5" cy="124.7" r=".4" fill="#fff"/>
<circle cx="48.5" cy="124.7" r=".4" fill="none" stroke="#000" stroke-width=".21"/>
<circle cx="48.5" cy="126.9" r=".4" fill="#fff"/>
<g fill="none" stroke="#000" stroke-width=".21">
<path d="M55.6 119.4v5.1M54.5 124.7l1.1 2.2v21l-.5 .8M54.1 147.9h2.9M54.7 147.9l-.6 .8M56.5 147.9l-.5 .8"/>
<circle cx="48.5" cy="126.9" r=".4"/>
</g>
<circle cx="55.7" cy="124.7" r=".4" fill="#fff"/>
<circle cx="55.7" cy="124.7" r=".4" fill="none" stroke="#000" stroke-width=".21"/>
<circle cx="55.7" cy="126.9" r=".39" fill="#fff"/>
<g fill="none" stroke="#000" stroke-width=".21">
<path d="M62.8 119.4v5.1M61.6 124.7l1.2 2.2M62.8 134.2v13.7l-.6 .8M61.2 147.9h3M61.8 147.9l-.6 .8M63.6 147.9l-.4 .8"/>
<circle cx="55.7" cy="126.9" r=".39"/>
</g>
<circle cx="62.8" cy="124.7" r=".4" fill="#fff"/>
<circle cx="62.8" cy="124.7" r=".4" fill="none" stroke="#000" stroke-width=".21"/>
<circle cx="62.8" cy="126.9" r=".4" fill="#fff"/>
<g fill="none" stroke="#000" stroke-width=".21">
<path d="M91.4 116.4v8.3M98.6 116.4v8.3M41.3 139v8.7M90.3 124.7l1.1 2.2"/>
<circle cx="62.8" cy="126.9" r=".4"/>
</g>
<circle cx="91.5" cy="124.7" r=".4" fill="#fff"/>
<circle cx="91.5" cy="124.7" r=".4" fill="none" stroke="#000" stroke-width=".21"/>
<circle cx="91.5" cy="126.9" r=".39" fill="#fff"/>
<g fill="none" stroke="#000" stroke-width=".21">
<path d="M97.4 124.7l1.2 2.2"/>
<circle cx="91.5" cy="126.9" r=".39"/>
</g>
<circle cx="98.6" cy="124.7" r=".4" fill="#fff"/>
<circle cx="98.6" cy="124.7" r=".4" fill="none" stroke="#000" stroke-width=".21"/>
<circle cx="98.6" cy="126.9" r=".4" fill="#fff"/>
<g fill="none" stroke="#000" stroke-width=".21">
<path d="M106.2 116.4v8.3M84.3 137.2l.4 .2-.8 .6 .8 .5-.8 .4 .8 .5-.8 .6 .4 .2M90.3 138.4h2.5M90.3 139h2.5M91.4 139v8.9M105 124.7l1.2 2.2M106.2 126.7v21.2l-.6 .8M104.6 147.9h3M105.2 147.9l-.6 .8M107 147.9l-.4 .8"/>
<circle cx="98.6" cy="126.9" r=".4"/>
</g>
<circle cx="106.2" cy="124.7" r=".4" fill="#fff"/>
<circle cx="106.2" cy="124.7" r=".4" fill="none" stroke="#000" stroke-width=".21"/>
<circle cx="106.2" cy="126.9" r=".4" fill="#fff"/>
<g fill="none" stroke="#000" stroke-width=".21">
<path d="M25.8 119.5l1.2 2.3v4.7l.4 .2-.8 .6 .8 .5-.8 .4 .8 .5-.8 .6 .4 .2"/>
<circle cx="106.2" cy="126.9" r=".4"/>
</g>
<circle cx="27" cy="119.6" r=".4" fill="#fff"/>
<circle cx="27" cy="119.6" r=".4" fill="none" stroke="#000" stroke-width=".21"/>
<circle cx="27" cy="121.7" r=".4" fill="#fff"/>
<g fill="none" stroke="#000" stroke-width=".21">
<path d="M83.1 124.7l1.2 2.2"/>
<circle cx="27" cy="121.7" r=".4"/>
</g>
<circle cx="84.3" cy="124.7" r=".4" fill="#fff"/>
<circle cx="84.3" cy="124.7" r=".4" fill="none" stroke="#000" stroke-width=".21"/>
<circle cx="84.3" cy="126.9" r=".4" fill="#fff"/>
<g fill="none" stroke="#000" stroke-width=".21">
<path d="M55.9 88.4h-7.4v25M58 95.4l-2.1 1.1h-7.4M58 88.4h23.9v27.8M58.3 96.5h3.1l.2-.4 .6 .8 .5-.8 .4 .8 .5-.8 .6 .8 .2-.4h17.5M47.3 138.4h2.6"/>
<circle cx="48.5" cy="113.4" r=".4"/>
<circle cx="81.9" cy="116.4" r=".39"/>
<circle cx="84.3" cy="126.9" r=".4"/>
</g>
<g fill="#000">
<circle cx="48.5" cy="113.4" r=".4"/>
<circle cx="81.9" cy="116.4" r=".39"/>
</g>
<path d="M47.9 139h1.2" fill="none" stroke="#000" stroke-width=".26"/>
<circle cx="58.2" cy="96.5" r=".4" fill="#fff"/>
<circle cx="58.2" cy="96.5" r=".4" fill="none" stroke="#000" stroke-width=".21"/>
<circle cx="56" cy="96.5" r=".4" fill="#fff"/>
<g fill="none" stroke="#000" stroke-width=".21">
<path d="M58 87.2l-2.1 1.2"/>
<circle cx="56" cy="96.5" r=".4"/>
</g>
<circle cx="58.2" cy="88.4" r=".4" fill="#fff"/>
<circle cx="58.2" cy="88.4" r=".4" fill="none" stroke="#000" stroke-width=".21"/>
<circle cx="56" cy="88.4" r=".4" fill="#fff"/>
<g fill="none" stroke="#000" stroke-width=".21">
<path d="M71.2 101.5h2.5M62.8 127.3v4l.4 .2-.8 .5 .8 .5-.8 .5 .8 .5-.8 .5 .4 .2M67.4 197.2v4.9M69.7 197.2h-4.9M143.4 197h5M146.1 197l-.1 4.9M33.4 219.7h2.4l-.4 1M33.8 219.7l-.4 1M34.6 215.3v4.4M34.8 219.7l-.4 1M39.7 201.5l-5.1-.1v12.8M39.8 201.5l.4-.6 .7 1.2 .8-1.2 .7 1.2 .8-1.2 .7 1.2 .4-.6"/>
<path d="M44 210h5.1M44 210v10.5M44.3 201.5h15.2M49.1 210l.4-.7 .7 1.4 .8-1.4 .8 1.4 .7-1.4 .8 1.4 .4-.7M50.5 201.5v-13.9h14.3l.4-.7 .8 1.4 .8-1.4 .9 1.4 .8-1.4 .8 1.4 .4-.7h10.7l.1 18.1M60 210h-6.3M67.4 209.3v5.2M69.7 214.5h-4.9M91.3 219.6h2.3l-.3 1M91.7 219.6l-.4 1M92.5 205.7v13.9M92.6 205.6l-18.3 .1"/>
<path d="M92.6 219.6l-.4 1M112.1 219.5l2.4 .1M112.5 219.5l-.4 1.1M113.5 219.5l-.4 1.1M114.5 219.5l-.4 1.1M118.4 201.3h-5.2v18.2M118.4 201.3l.4-.6 .8 1.2 .8-1.2 .7 1.2 .8-1.2 .7 1.2 .4-.6M127.9 209.8l.4-.7 .8 1.4 .7-1.4 .8 1.4 .7-1.4 .8 1.4 .4-.7M128 209.8h-5.1v10.8M129.2 201.3v-13.9h14.2l.5-.7 .8 1.5 .8-1.5 .9 1.5 .8-1.5 .8 1.5 .4-.8 10.7 .1v18M146.1 209.1l-.1 5.2M148.4 214.3l-5 .1"/>
<path d="M171.6 219.4h2.4l-.4 1.1M172 219.4l-.4 1.1M172.8 205.5h-19.8M172.9 205.5v13.9M173 219.4l-.3 1.1M42.8 220.5h2.3l-.4 1.1M43.2 220.5l-.4 1.1M44.2 220.5l-.4 1.1M121.6 220.1h2.4l-.3 1.1M122.1 220.1l-.5 1.1M123 220.1l-.4 1.1"/>
<circle cx="48.5" cy="96.5" r=".4"/>
<circle cx="56" cy="88.4" r=".4"/>
<circle cx="81.9" cy="96.5" r=".4"/>
<circle cx="55.7" cy="119.4" r=".39"/>
<circle cx="62.8" cy="119.4" r=".4"/>
<circle cx="67.4" cy="197.2" r=".66"/>
<circle cx="146" cy="196.9" r=".66"/>
<circle cx="50.5" cy="201.6" r=".62"/>
<circle cx="67.3" cy="214.5" r=".66"/>
<circle cx="80.3" cy="205.6" r=".61"/>
<circle cx="129.2" cy="201.4" r=".56"/>
<circle cx="145.9" cy="214.2" r=".66"/>
<circle cx="159.3" cy="205.5" r=".56"/>
</g>
<g fill="#000">
<circle cx="48.5" cy="96.5" r=".4"/>
<circle cx="81.9" cy="96.5" r=".4"/>
<circle cx="55.7" cy="119.4" r=".39"/>
<circle cx="62.8" cy="119.4" r=".4"/>
<circle cx="67.4" cy="197.2" r=".66"/>
<circle cx="146" cy="196.9" r=".66"/>
<circle cx="50.5" cy="201.6" r=".62"/>
<circle cx="67.3" cy="214.5" r=".66"/>
<circle cx="80.3" cy="205.6" r=".61"/>
<circle cx="129.2" cy="201.4" r=".56"/>
<circle cx="145.9" cy="214.2" r=".66"/>
<circle cx="159.3" cy="205.5" r=".56"/>
</g>
<path d="M59.5 198.3l15.5 7.4-15.5 7.5z" fill="#fff"/>
<path d="M59.5 198.3l15.5 7.4-15.5 7.5zM123 201.3h15.3M132.4 209.8h6.4" fill="none" stroke="#000" stroke-width=".21"/>
<path d="M138.3 198.1l15.5 7.4-15.5 7.5z" fill="#fff"/>
<path d="M138.3 198.1l15.5 7.4-15.5 7.5zM168 223.9h-16.8" fill="none" stroke="#000" stroke-width=".21"/>
<use href="#words"/>
</svg>
